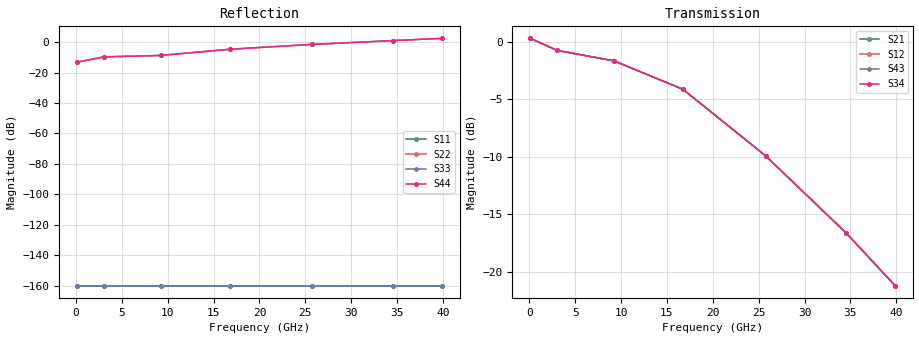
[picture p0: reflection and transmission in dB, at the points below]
! 26-Jun-2017 15:42:08
# Hz S RI R 50
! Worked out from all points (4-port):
!   319 points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, 125 MHz to 39.88 GHz, reference 50 ohm
!   strongest paths, dB at 125 MHz, 10 GHz, 20 GHz, 30 GHz, 39.88 GHz:
!     S43: 0.3, -1.7, -6.0, -13.1, -21.2
!     S21: 0.3, -1.7, -6.0, -13.1, -21.2
!     S42: -, -, -, -, -
!     S41: -, -, -, -, -
!     S32: -, -, -, -, -
!     S31: -, -, -, -, -
!   lowest |S11| = - dB at 125 MHz (marker M1), VSWR 1.00, Z = 50 + j0 ohm
!   |S11| at or under -10 dB: start of sweep to end of sweep
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1.25e8  0 0  1.034 -0.0271  0 0  0 0
        1.034 -0.0271  -0.2182 -0.0065  0 0  0 0
        0 0  0 0  0 0  1.034 -0.0271
        0 0  0 0  1.034 -0.0271  -0.2182 -0.0065
3e9  0 0  0.7943 -0.46  0 0  0 0
     0.7943 -0.46  -0.321 -0.0538  0 0  0 0
     0 0  0 0  0 0  0.7943 -0.46
     0 0  0 0  0.7943 -0.46  -0.321 -0.0538
9.25e9  0 0  0.1852 -0.8045  0 0  0 0
        0.1852 -0.8045  -0.3619 0.0379  0 0  0 0
        0 0  0 0  0 0  0.1852 -0.8045
        0 0  0 0  0.1852 -0.8045  -0.3619 0.0379
1.675e10  0 0  -0.5034 -0.3643  0 0  0 0
          -0.5034 -0.3643  -0.567 0.1268  0 0  0 0
          0 0  0 0  0 0  -0.5034 -0.3643
          0 0  0 0  -0.5034 -0.3643  -0.567 0.1268
2.575e10  0 0  -0.2613 0.1845  0 0  0 0
          -0.2613 0.1845  -0.6871 0.483  0 0  0 0
          0 0  0 0  0 0  -0.2613 0.1845
          0 0  0 0  -0.2613 0.1845  -0.6871 0.483
3.45e10  0 0  0.0188 0.1471  0 0  0 0
         0.0188 0.1471  -0.7462 0.8286  0 0  0 0
         0 0  0 0  0 0  0.0188 0.1471
         0 0  0 0  0.0188 0.1471  -0.7462 0.8286
3.9875e10  0 0  0.0665 0.0565  0 0  0 0
           0.0665 0.0565  -0.5616 1.198  0 0  0 0
           0 0  0 0  0 0  0.0665 0.0565
           0 0  0 0  0.0665 0.0565  -0.5616 1.198
